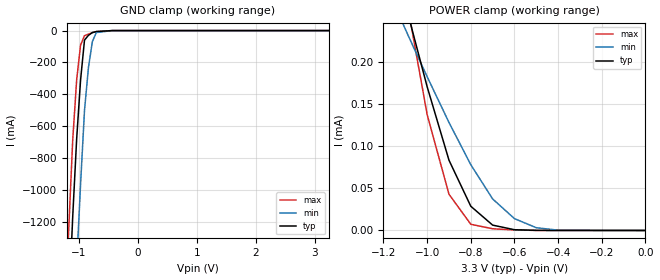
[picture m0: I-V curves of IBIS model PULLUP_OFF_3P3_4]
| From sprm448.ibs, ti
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|   Model Cell PULLUP_OFF_3P3
|PULLUP_OFF_3P3
[Model]   PULLUP_OFF_3P3_4
Model_type   Input
Polarity   Non-Inverting
Vinl =  0.8v
Vinh =  2v
C_comp   2.0027p   1.6434p   2.65p
[Model Spec]
Vinl   0.8v   0.8v   0.8v
Vinh   2v   2v   2v
[Temperature Range]   25   125   -40
[Voltage Range]   3.3   3   3.6
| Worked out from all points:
|   GND clamp passes 1 mA (typ) near -0.56 V on its own axis
|   POWER clamp passes 1 mA (typ) near -1.78 V on its own axis
[POWER_clamp]
|   voltage   I(typ)   I(min)   I(max)
-3.3V     2.698mA    1.574mA    4.07mA
-1.1V     269.3uA    238.9uA    282.5uA
-1.067V   236.4uA    220.1uA    234.2uA
-1V       170.6uA    182.5uA    137.5uA
-900mV    83.41uA    128.2uA    43.01uA
-800mV    28.73uA    78.04uA    7.36uA
-700mV    6.363uA    37.41uA    2.023uA
-600mV    885.1nA    14.06uA    630.3nA
-500mV    144.6nA    3.259uA    75.42nA
-400mV    11.24nA    347.9nA    2.763nA
-11.55fV  37.65pA    5.388nA    466.3fA
[GND_clamp]
|   voltage   I(typ)   I(min)   I(max)
-3.3V     -22.4A     -23.17A    -21.98A
-1.233V   -2.327A    -3.192A    -1.823A
-1.167V   -1.741A    -2.598A    -1.245A
-1.1V     -1.17A     -2.014A    -689.7mA
-1.033V   -680.3mA   -1.468A    -310.1mA
-966.7mV  -310.2mA   -963.5mA   -90.81mA
-900mV    -59.6mA    -500mA     -31.73mA
-833.3mV  -29.86mA   -231.2mA   -21.86mA
-766.7mV  -12.05mA   -68.59mA   -13.38mA
-700mV    -6.166mA   -12.25mA   -6.285mA
-433.3mV  -64.46uA   -229.1uA   -21.14uA
3.233V    36.75pA    14.8nA     407.1fA
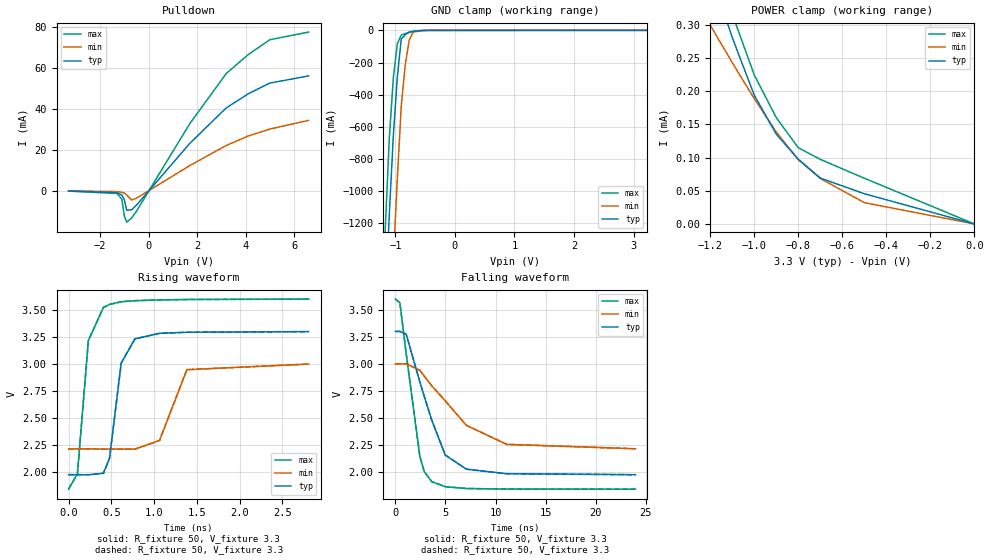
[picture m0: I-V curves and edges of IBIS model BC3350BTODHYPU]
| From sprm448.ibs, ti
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|BUFFER OPERATING IN WEAK PULLUP MODE.
|THIS IS AN OPEN DRAIN BUFFER.
|   Model Cell BC3350BTODHYPU
|BC3350BTODHYPU
[Model]   BC3350BTODHYPU
Model_type   I/O_open_drain
Polarity   Non-Inverting
Enable   Active-Low
Vinl =  0.8v
Vinh =  2v
Cref =  15.0000pF
Rref =  100.0000M
Vref =  0V
Vmeas =  1.65
C_comp   1.5587p   1.351p   1.9877p
[Model Spec]
Vinl   0.8v   0.8v   0.8v
Vinh   2v   2v   2v
[Temperature Range]   25   125   -40
[Voltage Range]   3.3   3   3.6
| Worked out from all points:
|   slope of the pulldown table from 0 to 0.495 V, typ, clamps not added: 71.1 ohm
|   GND clamp passes 1 mA (typ) near -0.56 V on its own axis
|   POWER clamp passes 1 mA (typ) near -1.78 V on its own axis
|   rising waveform, R_fixture 50, V_fixture 3.3: 20-80 % time 124ps typ, 163ps min, 113ps max; typ from 1.97 V to 3.3 V
|   rising waveform, R_fixture 50, V_fixture 3.3: 20-80 % time 124ps typ, 163ps min, 113ps max; typ from 1.97 V to 3.3 V
|   falling waveform, R_fixture 50, V_fixture 3.3: 20-80 % time 2.68ns typ, 4.51ns min, 1.46ns max; typ from 3.3 V to 1.97 V
|   falling waveform, R_fixture 50, V_fixture 3.3: 20-80 % time 2.68ns typ, 4.51ns min, 1.46ns max; typ from 3.3 V to 1.97 V
[POWER_clamp]
|   voltage   I(typ)   I(min)   I(max)
-3.3V     2.696mA    1.572mA    4.068mA
-1.2V     379.5uA    299.2uA    457.1uA
-1.167V   346.5uA    280.4uA    410.2uA
-1.133V   313.6uA    261.6uA    363.2uA
-1.1V     280.7uA    242.8uA    316.3uA
-1.067V   251.7uA    224.7uA    285.6uA
-1V       193.7uA    188.5uA    224.2uA
-900mV    135.1uA    138.3uA    160uA
-800mV    97.35uA    96.87uA    114.7uA
-700mV    69.06uA    68.46uA    97.2uA
-500mV    45.48uA    32.07uA    68.8uA
-11.55fV  35.7pA     5.21nA     532.9fA
[Pulldown]
|   voltage   I(typ)   I(min)   I(max)
-3.3V     -126.9uA   -70.66uA   -155.6uA
-1.3V     -917.2uA   -407.9uA   -1.338mA
-1.1V     -2.091mA   -723.6uA   -4.139mA
-1V       -4.433mA   -1.12mA    -12.26mA
-900mV    -9.514mA   -2.073mA   -15.35mA
-700mV    -9.274mA   -4.502mA   -13.31mA
-500mV    -7.052mA   -3.662mA   -10.01mA
1.7V      23.11mA    12.3mA     32.76mA
3.2V      40.42mA    22.07mA    57.19mA
4.1V      47.26mA    26.69mA    66.4mA
5V        52.57mA    30.11mA    73.74mA
6.6V      56.07mA    34.37mA    77.47mA
[GND_clamp]
|   voltage   I(typ)   I(min)   I(max)
-3.3V     -22.36A    -23.12A    -21.95A
-1.167V   -1.706A    -2.551A    -1.218A
-1.1V     -1.137A    -1.969A    -665.1mA
-1.033V   -652.7mA   -1.426A    -294.8mA
-966.7mV  -291.5mA   -925.6mA   -82.86mA
-900mV    -53.56mA   -469mA     -29.32mA
-833.3mV  -27.16mA   -213.8mA   -20.33mA
-766.7mV  -11.27mA   -61.23mA   -12.59mA
-700mV    -5.891mA   -11.15mA   -6.077mA
-566.7mV  -1.141mA   -1.938mA   -868.4uA
-433.3mV  -177.4uA   -292.4uA   -215uA
3.233V    -5.66uA    13.28uA    -45.87uA
[Ramp]
| variable   typ   min   max
dV/dt_f  0.7968664/2.684985n   0.4738974/4.535824n   1.057967/1.459634n
dV/dt_r  25.14559m/0.1214437n  17.33755m/0.1877949n  30.49901m/91.1875p
R_load = 50
[Rising Waveform]
R_fixture = 50
V_fixture = 3.3
V_fixture_min = 3
V_fixture_max = 3.6
|   time   V(typ)   V(min)   V(max)
0s        1.974V     2.211V     1.84V
104ps     1.974V     2.212V     1.981V
232ps     1.973V     2.212V     3.215V
408ps     1.987V     2.211V     3.52V
480ps     2.127V     2.211V     3.549V
616ps     3.006V     2.211V     3.573V
776ps     3.23V      2.21V      3.583V
1.064ns   3.281V     2.29V      3.59V
1.384ns   3.291V     2.945V     3.594V
2.808ns   3.297V     2.997V     3.598V
[Rising Waveform]
R_fixture = 50
V_fixture = 3.3
V_fixture_min = 3
V_fixture_max = 3.6
|   time   V(typ)   V(min)   V(max)
0s        1.974V     2.211V     1.84V
104ps     1.974V     2.212V     1.981V
232ps     1.973V     2.212V     3.215V
408ps     1.987V     2.211V     3.52V
480ps     2.127V     2.211V     3.549V
616ps     3.006V     2.211V     3.573V
776ps     3.23V      2.21V      3.583V
1.064ns   3.281V     2.29V      3.59V
1.384ns   3.291V     2.945V     3.594V
2.808ns   3.297V     2.997V     3.598V
[Falling Waveform]
R_fixture = 50
V_fixture = 3.3
V_fixture_min = 3
V_fixture_max = 3.6
|   time   V(typ)   V(min)   V(max)
0s        3.3V       3V         3.6V
448ps     3.3V       3V         3.566V
1.08ns    3.273V     3V         3.092V
2.44ns    2.833V     2.942V     2.145V
2.872ns   2.702V     2.887V     2.004V
3.624ns   2.48V      2.797V     1.91V
4.976ns   2.156V     2.658V     1.863V
7.08ns    2.025V     2.431V     1.846V
11.1ns    1.983V     2.255V     1.841V
23.97ns   1.974V     2.214V     1.84V
[Falling Waveform]
R_fixture = 50
V_fixture = 3.3
V_fixture_min = 3
V_fixture_max = 3.6
|   time   V(typ)   V(min)   V(max)
0s        3.3V       3V         3.6V
448ps     3.3V       3V         3.566V
1.08ns    3.273V     3V         3.092V
2.44ns    2.833V     2.942V     2.145V
2.872ns   2.702V     2.887V     2.004V
3.624ns   2.48V      2.797V     1.91V
4.976ns   2.156V     2.658V     1.863V
7.08ns    2.025V     2.431V     1.846V
11.1ns    1.983V     2.255V     1.841V
23.97ns   1.974V     2.214V     1.84V
